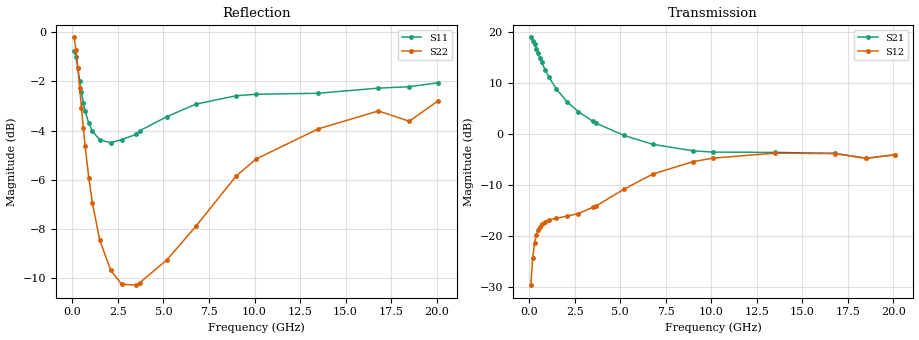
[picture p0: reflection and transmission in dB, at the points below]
!  Infineon Technologies AG
! BFR380L3 , PF131585-7, No.6, Th 09.10.01, soldered on pcb-board, measured with PP GSG850
!  Vce=1.75 V,  Ic=2.5 mA
! Common Emitter S-Parameters:  15. November 2001
#  GHz  S  MA  R  50
! f  S11  S21  S12  S22
! GHz  Mag  Ang  Mag  Ang  Mag  Ang  Mag  Ang
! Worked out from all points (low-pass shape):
!   201 points, 100 MHz to 20.1 GHz, reference 50 ohm
!   highest |S21| = 18.93 dB at 100 MHz (marker M1); lowest = -4.8 dB at 18.5 GHz (marker M2)
!   |S21| within 3 dB of the highest: start of sweep to 483 MHz
!   lowest |S11| = -4.5 dB at 2.1 GHz (marker M3), VSWR 3.95, Z = 12.7 - j1.66 ohm
!   |S11| at or under -10 dB: nowhere
!   |S22| runs from -10.4 to -0.2 dB; largest |S21 - S12| = 8.8
!   S11 on the Smith chart (normalised r, x): 100 MHz: 1.35, -5.29; 400 MHz: 0.32, -1.32; 1.1 GHz: 0.26, -0.38; 3.7 GHz: 0.24, +0.26; 9 GHz: 0.32, +1.05; 20.1 GHz: 0.98, +2.55
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0.1  0.9158 -20.2  8.842 166.0  0.0327 76.4  0.9767 -11.5
0.2  0.8894 -39.6  8.223 153.4  0.06097 68.1  0.9214 -22.1
0.3  0.8455 -57.2  7.539 142.1  0.08413 59.4  0.847 -31.0
0.4  0.7948 -72.3  6.825 132.5  0.1008 52.2  0.7708 -38.3
0.5  0.7543 -85.7  6.151 124.3  0.1132 46.7  0.7007 -44.1
0.6  0.719 -97.1  5.539 117.5  0.1222 42.3  0.6393 -48.8
0.7  0.69 -107.0  5.023 111.5  0.129 38.9  0.5872 -52.5
0.9  0.6532 -123.4  4.186 101.9  0.1376 34.4  0.5056 -58.4
1.1  0.6287 -136.2  3.573 94.1  0.1431 31.6  0.4495 -62.8
1.5  0.6045 -155.6  2.753 81.6  0.1486 29.7  0.3778 -69.5
2.1  0.5957 -175.9  2.055 67.3  0.1554 31.3  0.3281 -78.7
2.7  0.6048 169.0  1.655 55.6  0.1649 35.7  0.307 -89.0
3.5  0.6198 152.5  1.327 42.5  0.1896 42.0  0.3057 -103.1
3.7  0.6305 149.3  1.268 39.8  0.1965 43.0  0.3092 -107.7
5.2  0.6739 125.8  0.9648 21.8  0.2852 45.8  0.3444 -137.8
6.8  0.7145 105.3  0.7881 9.6  0.4033 39.0  0.4037 -170.8
8.999999  0.7429 84.5  0.681 -0.2  0.5326 22.7  0.5103 153.4
10.1  0.7481 76.3  0.6614 -4.3  0.5771 14.2  0.5525 137.8
13.5  0.7516 58.3  0.6571 -17.9  0.6457 -9.4  0.636 101.9
16.8  0.7699 47.0  0.642 -30.5  0.6395 -26.1  0.6918 78.0
18.5  0.7751 45.1  0.5767 -38.4  0.5732 -34.6  0.6591 72.1
20.1  0.7896 38.3  0.6209 -42.3  0.6255 -39.7  0.7262 61.0
